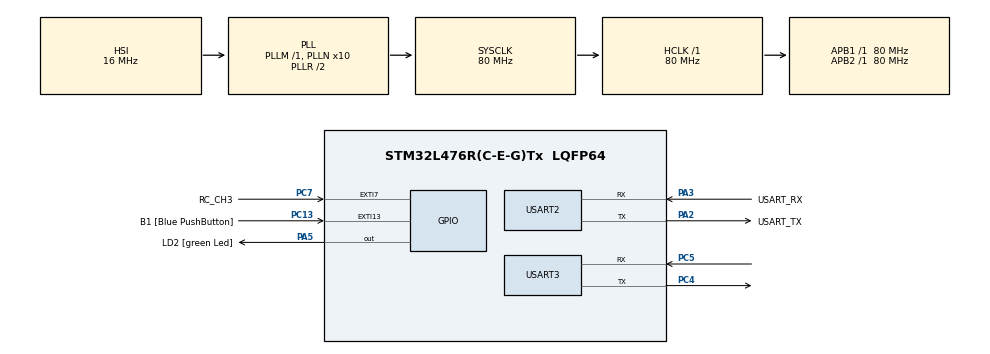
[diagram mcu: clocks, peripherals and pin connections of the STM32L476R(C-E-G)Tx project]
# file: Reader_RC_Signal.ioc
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FREERTOS.Tasks01=defaultTask,0,128,StartDefaultTask,Default,NULL
Mcu.Family=STM32L4
Mcu.Name=STM32L476R(C-E-G)Tx
Mcu.Package=LQFP64
NVIC.EXTI9_5_IRQn=true\:5\:0\:true\:false\:true\:false\:true\:true
NVIC.PriorityGroup=NVIC_PRIORITYGROUP_4
NVIC.TIM2_IRQn=true\:5\:0\:false\:false\:true\:true\:true\:true
PA13\ (JTMS-SWDIO).GPIO_Label=TMS
PA13\ (JTMS-SWDIO).Mode=Serial_Wire
PA13\ (JTMS-SWDIO).Signal=SYS_JTMS-SWDIO
PA14\ (JTCK-SWCLK).GPIO_Label=TCK
PA14\ (JTCK-SWCLK).Mode=Serial_Wire
PA14\ (JTCK-SWCLK).Signal=SYS_JTCK-SWCLK
PA2.GPIO_Label=USART_TX
PA2.GPIO_Mode=GPIO_MODE_AF_PP
PA2.GPIO_PuPd=GPIO_NOPULL
PA2.GPIO_Speed=GPIO_SPEED_FREQ_VERY_HIGH
PA2.Mode=Asynchronous
PA2.Signal=USART2_TX
PA3.GPIO_Label=USART_RX
PA3.GPIO_Mode=GPIO_MODE_AF_PP
PA3.GPIO_PuPd=GPIO_NOPULL
PA3.GPIO_Speed=GPIO_SPEED_FREQ_VERY_HIGH
PA3.Mode=Asynchronous
PA3.Signal=USART2_RX
PA5.GPIO_Label=LD2 [green Led]
PA5.GPIO_ModeDefaultOutputPP=GPIO_MODE_OUTPUT_PP
PA5.GPIO_PuPd=GPIO_NOPULL
PA5.GPIO_Speed=GPIO_SPEED_FREQ_LOW
PA5.Signal=GPIO_Output
PB3\ (JTDO-TRACESWO).GPIO_Label=SWO
PB3\ (JTDO-TRACESWO).Signal=SYS_JTDO-SWO
PC13.GPIO_Label=B1 [Blue PushButton]
PC13.GPIO_ModeDefaultEXTI=GPIO_MODE_IT_FALLING
PC13.GPIO_PuPd=GPIO_NOPULL
PC13.Signal=GPXTI13
PC14-OSC32_IN\ (PC14).Mode=LSE-External-Oscillator
PC14-OSC32_IN\ (PC14).Signal=RCC_OSC32_IN
PC15-OSC32_OUT\ (PC15).Mode=LSE-External-Oscillator
PC15-OSC32_OUT\ (PC15).Signal=RCC_OSC32_OUT
PC4.Mode=Asynchronous
PC4.Signal=USART3_TX
PC5.Mode=Asynchronous
PC5.Signal=USART3_RX
PC7.GPIO_Label=RC_CH3
PC7.GPIO_ModeDefaultEXTI=GPIO_MODE_IT_RISING_FALLING
PC7.Signal=GPXTI7
PH0-OSC_IN\ (PH0).Mode=HSE-External-Oscillator
PH0-OSC_IN\ (PH0).Signal=RCC_OSC_IN
PH1-OSC_OUT\ (PH1).Mode=HSE-External-Oscillator
PH1-OSC_OUT\ (PH1).Signal=RCC_OSC_OUT
ProjectManager.HeapSize=0x200
ProjectManager.StackSize=0x400
ProjectManager.TargetToolchain=SW4STM32
RCC.ADCFreq_Value=64000000
RCC.AHBFreq_Value=80000000
RCC.APB1Freq_Value=80000000
RCC.APB1TimFreq_Value=80000000
RCC.APB2Freq_Value=80000000
RCC.APB2TimFreq_Value=80000000
RCC.CortexFreq_Value=80000000
RCC.HCLKFreq_Value=80000000
RCC.HSE_VALUE=8000000
RCC.HSI_VALUE=16000000
RCC.MSI_VALUE=4000000
RCC.PLLN=10
RCC.PLLSourceVirtual=RCC_PLLSOURCE_HSI
RCC.PREFETCH_ENABLE=1
RCC.SYSCLKFreq_VALUE=80000000
RCC.SYSCLKSource=RCC_SYSCLKSOURCE_PLLCLK
RCC.USBFreq_Value=64000000
RCC.VCOOutputFreq_Value=160000000
TIM2.Period=100000
TIM2.Prescaler=4799
USART2.VirtualMode-Asynchronous=VM_ASYNC
USART3.VirtualMode-Asynchronous=VM_ASYNC
VP_FREERTOS_VS_CMSIS_V1.Mode=CMSIS_V1
VP_TIM2_VS_ClockSourceINT.Mode=Internal
board=NUCLEO-L476RG

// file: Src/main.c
/* USER CODE BEGIN Header */
/**
  ******************************************************************************
  * @file           : main.c
  * @brief          : Main program body
  ******************************************************************************
  * @attention
  *
  * <h2><center>&copy; Copyright (c) 2019 STMicroelectronics.
  * All rights reserved.</center></h2>
  *
  * This software component is licensed by ST under Ultimate Liberty license
  * SLA0044, the "License"; You may not use this file except in compliance with
  * the License. You may obtain a copy of the License at:
  *                             www.st.com/SLA0044
  *
  ******************************************************************************
  */
/* USER CODE END Header */

#include "main.h"
#include "cmsis_os.h"

TIM_HandleTypeDef htim2;

UART_HandleTypeDef huart2;
UART_HandleTypeDef huart3;

osThreadId defaultTaskHandle;
/* USER CODE BEGIN PV */
long pulse_width[HYDRO_NB_RC_CH];
long pulse_start[HYDRO_NB_RC_CH];

/* USER CODE END PV */

void SystemClock_Config(void);
static void MX_GPIO_Init(void);
static void MX_USART2_UART_Init(void);
static void MX_USART3_UART_Init(void);
static void MX_TIM2_Init(void);
void StartDefaultTask(void const * argument);

/* USER CODE BEGIN 0 */
static void debugPrint(UART_HandleTypeDef *huart, char _out[]){
  HAL_UART_Transmit(huart, (uint8_t *) _out, strlen(_out), 10);
}

static void debugPrintln(UART_HandleTypeDef *huart, char _out[]){
  HAL_UART_Transmit(huart, (uint8_t *) _out, strlen(_out), 10);
  char newline[2] = "\r\n";
  HAL_UART_Transmit(huart, (uint8_t *) newline, 2, 10);
}
/* USER CODE END 0 */

int main(void)
{

  /* MCU Configuration--------------------------------------------------------*/

  /* Reset of all peripherals, Initializes the Flash interface and the Systick. */
  HAL_Init();

  /* Configure the system clock */
  SystemClock_Config();

  /* Initialize all configured peripherals */
  MX_GPIO_Init();
  MX_USART2_UART_Init();
  MX_USART3_UART_Init();
  MX_TIM2_Init();

  /* Create the thread(s) */
  /* definition and creation of defaultTask */
  osThreadDef(defaultTask, StartDefaultTask, osPriorityNormal, 0, 128);
  defaultTaskHandle = osThreadCreate(osThread(defaultTask), NULL);

  /* Start scheduler */
  osKernelStart();

  /* We should never get here as control is now taken by the scheduler */

  /* Infinite loop */
  /* USER CODE BEGIN WHILE */
  while (1)
  {
//	  debugPrint(&huart2, "oi, mate!");       // print
//	  debugPrint(&huart2, "\r\n");            // manual new line
//	  debugPrintln(&huart2, "how are you?");  // print full line
//	  if(send_pulse){
//		debugPrint(&huart2, "Pulse Width: ");
//		char buffer[32];
//		sprintf(buffer, "%ld", pulse_width);
//		debugPrintln(&huart2, buffer);
//		send_pulse = false;
//	  }
    /* USER CODE END WHILE */

  }
}

void SystemClock_Config(void)
{
  RCC_OscInitTypeDef RCC_OscInitStruct = {0};
  RCC_ClkInitTypeDef RCC_ClkInitStruct = {0};
  RCC_PeriphCLKInitTypeDef PeriphClkInit = {0};

  /** Initializes the CPU, AHB and APB busses clocks
  */
  RCC_OscInitStruct.OscillatorType = RCC_OSCILLATORTYPE_HSI;
  RCC_OscInitStruct.HSIState = RCC_HSI_ON;
  RCC_OscInitStruct.HSICalibrationValue = RCC_HSICALIBRATION_DEFAULT;
  RCC_OscInitStruct.PLL.PLLState = RCC_PLL_ON;
  RCC_OscInitStruct.PLL.PLLSource = RCC_PLLSOURCE_HSI;
  RCC_OscInitStruct.PLL.PLLM = 1;
  RCC_OscInitStruct.PLL.PLLN = 10;
  RCC_OscInitStruct.PLL.PLLP = RCC_PLLP_DIV7;
  RCC_OscInitStruct.PLL.PLLQ = RCC_PLLQ_DIV2;
  RCC_OscInitStruct.PLL.PLLR = RCC_PLLR_DIV2;
  if (HAL_RCC_OscConfig(&RCC_OscInitStruct) != HAL_OK)
  {
    Error_Handler();
  }
  /** Initializes the CPU, AHB and APB busses clocks
  */
  RCC_ClkInitStruct.ClockType = RCC_CLOCKTYPE_HCLK|RCC_CLOCKTYPE_SYSCLK
                              |RCC_CLOCKTYPE_PCLK1|RCC_CLOCKTYPE_PCLK2;
  RCC_ClkInitStruct.SYSCLKSource = RCC_SYSCLKSOURCE_PLLCLK;
  RCC_ClkInitStruct.AHBCLKDivider = RCC_SYSCLK_DIV1;
  RCC_ClkInitStruct.APB1CLKDivider = RCC_HCLK_DIV1;
  RCC_ClkInitStruct.APB2CLKDivider = RCC_HCLK_DIV1;

  if (HAL_RCC_ClockConfig(&RCC_ClkInitStruct, FLASH_LATENCY_4) != HAL_OK)
  {
    Error_Handler();
  }
  PeriphClkInit.PeriphClockSelection = RCC_PERIPHCLK_USART2|RCC_PERIPHCLK_USART3;
  PeriphClkInit.Usart2ClockSelection = RCC_USART2CLKSOURCE_PCLK1;
  PeriphClkInit.Usart3ClockSelection = RCC_USART3CLKSOURCE_PCLK1;
  if (HAL_RCCEx_PeriphCLKConfig(&PeriphClkInit) != HAL_OK)
  {
    Error_Handler();
  }
  /** Configure the main internal regulator output voltage
  */
  if (HAL_PWREx_ControlVoltageScaling(PWR_REGULATOR_VOLTAGE_SCALE1) != HAL_OK)
  {
    Error_Handler();
  }
}

static void MX_TIM2_Init(void)
{

  TIM_ClockConfigTypeDef sClockSourceConfig = {0};
  TIM_MasterConfigTypeDef sMasterConfig = {0};

  htim2.Instance = TIM2;
  htim2.Init.Prescaler = 79;
  htim2.Init.CounterMode = TIM_COUNTERMODE_UP;
  htim2.Init.Period = 100000;
  htim2.Init.ClockDivision = TIM_CLOCKDIVISION_DIV1;
  htim2.Init.AutoReloadPreload = TIM_AUTORELOAD_PRELOAD_DISABLE;
  if (HAL_TIM_Base_Init(&htim2) != HAL_OK)
  {
    Error_Handler();
  }
  sClockSourceConfig.ClockSource = TIM_CLOCKSOURCE_INTERNAL;
  if (HAL_TIM_ConfigClockSource(&htim2, &sClockSourceConfig) != HAL_OK)
  {
    Error_Handler();
  }
  sMasterConfig.MasterOutputTrigger = TIM_TRGO_RESET;
  sMasterConfig.MasterSlaveMode = TIM_MASTERSLAVEMODE_DISABLE;
  if (HAL_TIMEx_MasterConfigSynchronization(&htim2, &sMasterConfig) != HAL_OK)
  {
    Error_Handler();
  }
  /* USER CODE BEGIN TIM2_Init 2 */
  if (HAL_TIM_Base_Start(&htim2) != HAL_OK)
    {
      Error_Handler();
    }
  /* USER CODE END TIM2_Init 2 */

}

static void MX_USART2_UART_Init(void)
{

  huart2.Instance = USART2;
  huart2.Init.BaudRate = 115200;
  huart2.Init.WordLength = UART_WORDLENGTH_8B;
  huart2.Init.StopBits = UART_STOPBITS_1;
  huart2.Init.Parity = UART_PARITY_NONE;
  huart2.Init.Mode = UART_MODE_TX_RX;
  huart2.Init.HwFlowCtl = UART_HWCONTROL_NONE;
  huart2.Init.OverSampling = UART_OVERSAMPLING_16;
  huart2.Init.OneBitSampling = UART_ONE_BIT_SAMPLE_DISABLE;
  huart2.AdvancedInit.AdvFeatureInit = UART_ADVFEATURE_NO_INIT;
  if (HAL_UART_Init(&huart2) != HAL_OK)
  {
    Error_Handler();
  }

}

static void MX_USART3_UART_Init(void)
{

  huart3.Instance = USART3;
  huart3.Init.BaudRate = 115200;
  huart3.Init.WordLength = UART_WORDLENGTH_8B;
  huart3.Init.StopBits = UART_STOPBITS_1;
  huart3.Init.Parity = UART_PARITY_NONE;
  huart3.Init.Mode = UART_MODE_TX_RX;
  huart3.Init.HwFlowCtl = UART_HWCONTROL_NONE;
  huart3.Init.OverSampling = UART_OVERSAMPLING_16;
  huart3.Init.OneBitSampling = UART_ONE_BIT_SAMPLE_DISABLE;
  huart3.AdvancedInit.AdvFeatureInit = UART_ADVFEATURE_NO_INIT;
  if (HAL_UART_Init(&huart3) != HAL_OK)
  {
    Error_Handler();
  }

}

static void MX_GPIO_Init(void)
{
  GPIO_InitTypeDef GPIO_InitStruct = {0};

  /* GPIO Ports Clock Enable */
  __HAL_RCC_GPIOC_CLK_ENABLE();
  __HAL_RCC_GPIOH_CLK_ENABLE();
  __HAL_RCC_GPIOA_CLK_ENABLE();
  __HAL_RCC_GPIOB_CLK_ENABLE();

  /*Configure GPIO pin Output Level */
  HAL_GPIO_WritePin(LD2_GPIO_Port, LD2_Pin, GPIO_PIN_RESET);

  /*Configure GPIO pin : B1_Pin */
  GPIO_InitStruct.Pin = B1_Pin;
  GPIO_InitStruct.Mode = GPIO_MODE_IT_FALLING;
  GPIO_InitStruct.Pull = GPIO_NOPULL;
  HAL_GPIO_Init(B1_GPIO_Port, &GPIO_InitStruct);

  /*Configure GPIO pin : LD2_Pin */
  GPIO_InitStruct.Pin = LD2_Pin;
  GPIO_InitStruct.Mode = GPIO_MODE_OUTPUT_PP;
  GPIO_InitStruct.Pull = GPIO_NOPULL;
  GPIO_InitStruct.Speed = GPIO_SPEED_FREQ_LOW;
  HAL_GPIO_Init(LD2_GPIO_Port, &GPIO_InitStruct);

  /*Configure GPIO pin : RC_CH2_Pin */
  GPIO_InitStruct.Pin = RC_CH2_Pin;
  GPIO_InitStruct.Mode = GPIO_MODE_IT_RISING_FALLING;
  GPIO_InitStruct.Pull = GPIO_NOPULL;
  HAL_GPIO_Init(RC_CH3_GPIO_Port, &GPIO_InitStruct);

  /*Configure GPIO pin : RC_CH3_Pin */
  GPIO_InitStruct.Pin = RC_CH3_Pin;
  GPIO_InitStruct.Mode = GPIO_MODE_IT_RISING_FALLING;
  GPIO_InitStruct.Pull = GPIO_NOPULL;
  HAL_GPIO_Init(RC_CH3_GPIO_Port, &GPIO_InitStruct);

  /*Configure GPIO pin : RC_CH3_Pin */
  GPIO_InitStruct.Pin = RC_CH4_Pin;
  GPIO_InitStruct.Mode = GPIO_MODE_IT_RISING_FALLING;
  GPIO_InitStruct.Pull = GPIO_NOPULL;
  HAL_GPIO_Init(RC_CH4_GPIO_Port, &GPIO_InitStruct);

  /*Configure GPIO pin : MAX485_Pin */
  GPIO_InitStruct.Pin = GPIO_PIN_10;
  GPIO_InitStruct.Mode = GPIO_MODE_OUTPUT_PP;
  GPIO_InitStruct.Pull = GPIO_NOPULL;
  GPIO_InitStruct.Speed = GPIO_SPEED_FREQ_MEDIUM;
  HAL_GPIO_Init(GPIOC, &GPIO_InitStruct);

  /* EXTI interrupt init*/
  HAL_NVIC_SetPriority(EXTI9_5_IRQn, 5, 0);
  HAL_NVIC_EnableIRQ(EXTI9_5_IRQn);

}

void StartDefaultTask(void const * argument)
{

  /* USER CODE BEGIN 5 */
  /* Infinite loop */
	for(;;)
	{
		debugPrint(&huart2, "pulse: ");
		char buffer[32];
		sprintf(buffer, "%ld\t%ld\t%ld", pulse_width[0], pulse_width[1], pulse_width[2]);
		debugPrintln(&huart2, buffer);
		HAL_GPIO_WritePin(MAX485_GPIO_Port, MAX485_Pin, SET);
		osDelay(2);
		debugPrint(&huart3, "C");
		osDelay(2);
		char in[8];
		HAL_UART_Receive(&huart3, (uint8_t *)in, 8, 10);
		debugPrintln(&huart2, in);
		HAL_GPIO_WritePin(MAX485_GPIO_Port, MAX485_Pin, RESET);
	}
  /* USER CODE END 5 */
}

void Error_Handler(void)
{
}

/************************ (C) COPYRIGHT STMicroelectronics *****END OF FILE****/
